VERSION 5.7 ;
  NOWIREEXTENSIONATPIN ON ;
  DIVIDERCHAR "/" ;
  BUSBITCHARS "[]" ;
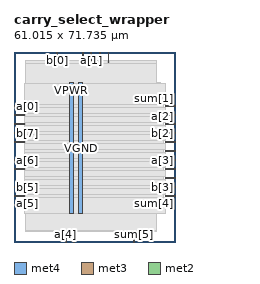
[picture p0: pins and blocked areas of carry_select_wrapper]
MACRO carry_select_wrapper
  CLASS BLOCK ;
  FOREIGN carry_select_wrapper ;
  ORIGIN 0.000 0.000 ;
  SIZE 61.015 BY 71.735 ;
  PIN VGND
    DIRECTION INOUT ;
    USE GROUND ;
    PORT
      LAYER met4 ;
        RECT 24.340 10.640 25.940 60.080 ;
    END
  END VGND
  PIN VPWR
    DIRECTION INOUT ;
    USE POWER ;
    PORT
      LAYER met4 ;
        RECT 21.040 10.640 22.640 60.080 ;
    END
  END VPWR
  PIN a[0]
    DIRECTION INPUT ;
    USE SIGNAL ;
    ANTENNAGATEAREA 0.196500 ;
    PORT
      LAYER met3 ;
        RECT 0.000 51.040 4.000 51.640 ;
    END
  END a[0]
  PIN a[1]
    DIRECTION INPUT ;
    USE SIGNAL ;
    ANTENNAGATEAREA 0.196500 ;
    PORT
      LAYER met2 ;
        RECT 29.070 67.735 29.350 71.735 ;
    END
  END a[1]
  PIN a[2]
    DIRECTION INPUT ;
    USE SIGNAL ;
    ANTENNAGATEAREA 0.196500 ;
    PORT
      LAYER met3 ;
        RECT 57.015 44.240 61.015 44.840 ;
    END
  END a[2]
  PIN a[3]
    DIRECTION INPUT ;
    USE SIGNAL ;
    ANTENNAGATEAREA 0.196500 ;
    PORT
      LAYER met3 ;
        RECT 57.015 30.640 61.015 31.240 ;
    END
  END a[3]
  PIN a[4]
    DIRECTION INPUT ;
    USE SIGNAL ;
    ANTENNAGATEAREA 0.196500 ;
    PORT
      LAYER met2 ;
        RECT 19.410 0.000 19.690 4.000 ;
    END
  END a[4]
  PIN a[5]
    DIRECTION INPUT ;
    USE SIGNAL ;
    ANTENNAGATEAREA 0.196500 ;
    PORT
      LAYER met3 ;
        RECT 0.000 17.040 4.000 17.640 ;
    END
  END a[5]
  PIN a[6]
    DIRECTION INPUT ;
    USE SIGNAL ;
    ANTENNAGATEAREA 0.196500 ;
    PORT
      LAYER met3 ;
        RECT 0.000 30.640 4.000 31.240 ;
    END
  END a[6]
  PIN a[7]
    DIRECTION INPUT ;
    USE SIGNAL ;
    ANTENNAGATEAREA 0.196500 ;
    PORT
      LAYER met3 ;
        RECT 0.000 37.440 4.000 38.040 ;
    END
  END a[7]
  PIN b[0]
    DIRECTION INPUT ;
    USE SIGNAL ;
    ANTENNAGATEAREA 0.196500 ;
    PORT
      LAYER met2 ;
        RECT 16.190 67.735 16.470 71.735 ;
    END
  END b[0]
  PIN b[1]
    DIRECTION INPUT ;
    USE SIGNAL ;
    ANTENNAGATEAREA 0.196500 ;
    PORT
      LAYER met2 ;
        RECT 35.510 67.735 35.790 71.735 ;
    END
  END b[1]
  PIN b[2]
    DIRECTION INPUT ;
    USE SIGNAL ;
    ANTENNAGATEAREA 0.196500 ;
    PORT
      LAYER met3 ;
        RECT 57.015 40.840 61.015 41.440 ;
    END
  END b[2]
  PIN b[3]
    DIRECTION INPUT ;
    USE SIGNAL ;
    ANTENNAGATEAREA 0.196500 ;
    PORT
      LAYER met3 ;
        RECT 57.015 20.440 61.015 21.040 ;
    END
  END b[3]
  PIN b[4]
    DIRECTION INPUT ;
    USE SIGNAL ;
    ANTENNAGATEAREA 0.196500 ;
    PORT
      LAYER met2 ;
        RECT 22.630 0.000 22.910 4.000 ;
    END
  END b[4]
  PIN b[5]
    DIRECTION INPUT ;
    USE SIGNAL ;
    ANTENNAGATEAREA 0.196500 ;
    PORT
      LAYER met3 ;
        RECT 0.000 20.440 4.000 21.040 ;
    END
  END b[5]
  PIN b[6]
    DIRECTION INPUT ;
    USE SIGNAL ;
    ANTENNAGATEAREA 0.196500 ;
    PORT
      LAYER met3 ;
        RECT 0.000 27.240 4.000 27.840 ;
    END
  END b[6]
  PIN b[7]
    DIRECTION INPUT ;
    USE SIGNAL ;
    ANTENNAGATEAREA 0.196500 ;
    PORT
      LAYER met3 ;
        RECT 0.000 40.840 4.000 41.440 ;
    END
  END b[7]
  PIN cin
    DIRECTION INPUT ;
    USE SIGNAL ;
    ANTENNAGATEAREA 0.196500 ;
    PORT
      LAYER met3 ;
        RECT 0.000 47.640 4.000 48.240 ;
    END
  END cin
  PIN clk
    DIRECTION INPUT ;
    USE SIGNAL ;
    ANTENNAGATEAREA 0.852000 ;
    PORT
      LAYER met3 ;
        RECT 0.000 44.240 4.000 44.840 ;
    END
  END clk
  PIN cout
    DIRECTION OUTPUT ;
    USE SIGNAL ;
    ANTENNADIFFAREA 0.445500 ;
    PORT
      LAYER met2 ;
        RECT 25.850 67.735 26.130 71.735 ;
    END
  END cout
  PIN reset
    DIRECTION INPUT ;
    USE SIGNAL ;
    ANTENNAGATEAREA 0.196500 ;
    PORT
      LAYER met3 ;
        RECT 57.015 47.640 61.015 48.240 ;
    END
  END reset
  PIN sum[0]
    DIRECTION OUTPUT ;
    USE SIGNAL ;
    ANTENNADIFFAREA 0.445500 ;
    PORT
      LAYER met2 ;
        RECT 32.290 67.735 32.570 71.735 ;
    END
  END sum[0]
  PIN sum[1]
    DIRECTION OUTPUT ;
    USE SIGNAL ;
    ANTENNADIFFAREA 0.445500 ;
    PORT
      LAYER met3 ;
        RECT 57.015 51.040 61.015 51.640 ;
    END
  END sum[1]
  PIN sum[2]
    DIRECTION OUTPUT ;
    USE SIGNAL ;
    ANTENNADIFFAREA 0.445500 ;
    PORT
      LAYER met3 ;
        RECT 57.015 34.040 61.015 34.640 ;
    END
  END sum[2]
  PIN sum[3]
    DIRECTION OUTPUT ;
    USE SIGNAL ;
    ANTENNADIFFAREA 0.445500 ;
    PORT
      LAYER met3 ;
        RECT 57.015 23.840 61.015 24.440 ;
    END
  END sum[3]
  PIN sum[4]
    DIRECTION OUTPUT ;
    USE SIGNAL ;
    ANTENNADIFFAREA 0.445500 ;
    PORT
      LAYER met3 ;
        RECT 57.015 17.040 61.015 17.640 ;
    END
  END sum[4]
  PIN sum[5]
    DIRECTION OUTPUT ;
    USE SIGNAL ;
    ANTENNADIFFAREA 0.445500 ;
    PORT
      LAYER met2 ;
        RECT 45.170 0.000 45.450 4.000 ;
    END
  END sum[5]
  PIN sum[6]
    DIRECTION OUTPUT ;
    USE SIGNAL ;
    ANTENNADIFFAREA 0.445500 ;
    PORT
      LAYER met3 ;
        RECT 57.015 27.240 61.015 27.840 ;
    END
  END sum[6]
  PIN sum[7]
    DIRECTION OUTPUT ;
    USE SIGNAL ;
    ANTENNADIFFAREA 0.445500 ;
    PORT
      LAYER met3 ;
        RECT 57.015 37.440 61.015 38.040 ;
    END
  END sum[7]
  OBS
      LAYER nwell ;
        RECT 5.330 10.795 55.390 59.925 ;
      LAYER li1 ;
        RECT 5.520 10.795 55.200 59.925 ;
      LAYER met1 ;
        RECT 4.210 10.640 55.200 60.080 ;
      LAYER met2 ;
        RECT 4.230 67.455 15.910 68.410 ;
        RECT 16.750 67.455 25.570 68.410 ;
        RECT 26.410 67.455 28.790 68.410 ;
        RECT 29.630 67.455 32.010 68.410 ;
        RECT 32.850 67.455 35.230 68.410 ;
        RECT 36.070 67.455 53.730 68.410 ;
        RECT 4.230 4.280 53.730 67.455 ;
        RECT 4.230 4.000 19.130 4.280 ;
        RECT 19.970 4.000 22.350 4.280 ;
        RECT 23.190 4.000 44.890 4.280 ;
        RECT 45.730 4.000 53.730 4.280 ;
      LAYER met3 ;
        RECT 3.990 52.040 57.015 60.005 ;
        RECT 4.400 50.640 56.615 52.040 ;
        RECT 3.990 48.640 57.015 50.640 ;
        RECT 4.400 47.240 56.615 48.640 ;
        RECT 3.990 45.240 57.015 47.240 ;
        RECT 4.400 43.840 56.615 45.240 ;
        RECT 3.990 41.840 57.015 43.840 ;
        RECT 4.400 40.440 56.615 41.840 ;
        RECT 3.990 38.440 57.015 40.440 ;
        RECT 4.400 37.040 56.615 38.440 ;
        RECT 3.990 35.040 57.015 37.040 ;
        RECT 3.990 33.640 56.615 35.040 ;
        RECT 3.990 31.640 57.015 33.640 ;
        RECT 4.400 30.240 56.615 31.640 ;
        RECT 3.990 28.240 57.015 30.240 ;
        RECT 4.400 26.840 56.615 28.240 ;
        RECT 3.990 24.840 57.015 26.840 ;
        RECT 3.990 23.440 56.615 24.840 ;
        RECT 3.990 21.440 57.015 23.440 ;
        RECT 4.400 20.040 56.615 21.440 ;
        RECT 3.990 18.040 57.015 20.040 ;
        RECT 4.400 16.640 56.615 18.040 ;
        RECT 3.990 10.715 57.015 16.640 ;
  END
END carry_select_wrapper
END LIBRARY

